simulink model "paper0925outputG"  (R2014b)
settings: Solver=ode3  StartTime=0.0  StopTime=24  FixedStep=1e-2  RelTol=1e-3
libraries: simulink x1

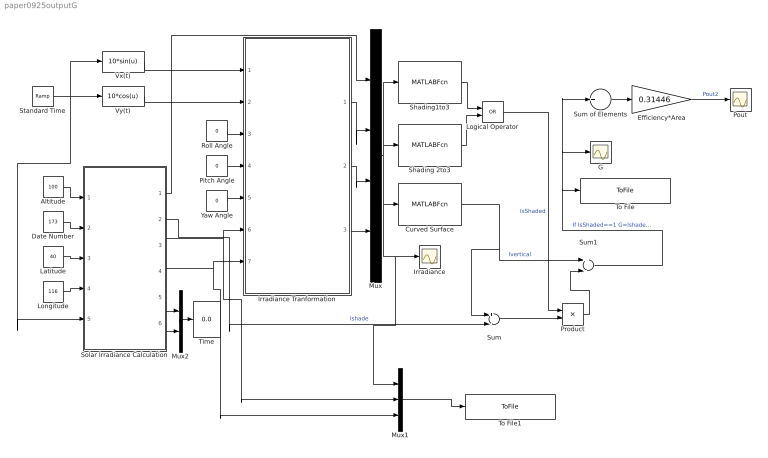
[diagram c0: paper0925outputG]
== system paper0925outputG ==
  Altitude : Constant  Value=100
  Curved Surface : MATLABFcn  MATLABFcn=calculateIcurve  OutputDimensions=18  OutputSignalType=real
  Date Number : Constant  Value=173
  Efficiency*Area : Gain  Gain=0.31446
  G : Scope
  Irradiance : Scope
  Irradiance Tranformation : MATLAB Function  TreatAsAtomicUnit=on
  Latitude : Constant  Value=40
  Logical Operator : Logic  Operator=OR  AllPortsSameDT=off  OutDataTypeStr=boolean
  Longitude : Constant  Value=116
  Mux : Mux  Inputs=[1 1 1 1]
  Mux1 : Mux  Inputs=3
  Mux2 : Mux  Inputs=2
  Pitch Angle : Constant  Value=0
  Pout : Scope
  Product : Product
  Roll Angle : Constant  Value=0
  Shading 2to3 : MATLABFcn  MATLABFcn=calculateIsShaded2  OutputDimensions=18  OutputSignalType=real
  Shading1to3 : MATLABFcn  MATLABFcn=calculateIsShaded1  OutputDimensions=18  OutputSignalType=real
  Solar Irradiance Calculation : MATLAB Function  TreatAsAtomicUnit=on
  Standard Time : simulink/Sources/Ramp  slope=1  start=0  X0=0
  Sum : Sum  Inputs=+-
  Sum of Elements : Sum  Inputs=+
  Sum1 : Sum  Inputs=+-
  Time : Display
  To File : ToFile  Filename=Goverlap100_4.mat  MatrixName=Ir0906
  To File1 : ToFile  Filename=XYZsolar.mat  MatrixName=Ir0906
  Vx(t) : Fcn  Expr=10*sin(u)
  Vy(t) : Fcn  Expr=10*cos(u)
  Yaw Angle : Constant  Value=0
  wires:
  Altitude/1 -> Solar Irradiance Calculation/1(H)
  Date Number/1 -> Solar Irradiance Calculation/2(dn)
  Latitude/1 -> Solar Irradiance Calculation/3(Lati)
  Longitude/1 -> Solar Irradiance Calculation/4(Long)
  Solar Irradiance Calculation/4(Azimuth) -> Mux1/3, Irradiance Tranformation/7(Azimuth)
  Mux2/1 -> Time/1
  Solar Irradiance Calculation/1(I) -> Mux/1
  Solar Irradiance Calculation/5(Tsunrise) -> Mux2/1
  Solar Irradiance Calculation/6(Tsunset) -> Mux2/2
  Irradiance Tranformation/1(Xsolar) -> Mux/2
  Irradiance Tranformation/2(Ysolar) -> Mux/3
  Irradiance Tranformation/3(Zsolar) -> Mux/4
  Vx(t)/1 -> Irradiance Tranformation/1(Vx)
  Vy(t)/1 -> Irradiance Tranformation/2(Vy)
  Pitch Angle/1 -> Irradiance Tranformation/4(Pitch)
  Yaw Angle/1 -> Irradiance Tranformation/5(Yaw)
  Standard Time/1 -> Vx(t)/1, Vy(t)/1, Solar Irradiance Calculation/5(ts)
  Roll Angle/1 -> Irradiance Tranformation/3(Roll)
  Sum of Elements/1 -> Efficiency*Area/1
  Shading1to3/1 -> Logical Operator/1
  Mux/1 -> Mux1/1, Irradiance/1, Curved Surface/1, Shading1to3/1, Shading 2to3/1
  Solar Irradiance Calculation/2(Ishade) -> Sum/2  "Ishade"
  Shading 2to3/1 -> Logical Operator/2
  Curved Surface/1 -> Sum1/1, Sum/1  "Ivertical"
  Logical Operator/1 -> Product/1  "IsShaded"
  Sum/1 -> Product/2
  Product/1 -> Sum1/2
  Sum1/1 -> To File/1, Sum of Elements/1, G/1  "If IsShaded==1 G=Ishaded; else G=Ivertical"
  Efficiency*Area/1 -> Pout/1  "Pout2"
  Mux1/1 -> To File1/1
  Solar Irradiance Calculation/3(Elevation) -> Mux1/2, Irradiance Tranformation/6(Elevation)

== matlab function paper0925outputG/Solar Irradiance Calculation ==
function [I,Ishade,Elevation,Azimuth,Tsunrise,Tsunset] = fcn(H,dn,Lati,Long,ts)
%#codegen
%输入飞行参数（经Long、纬度Lati、高度H、日期dn、标准时间ts）
%输出照射情况（高度角Elevatio、方位角Azimuth、垂直辐照度I)
%输出一天的统计情况

Isc =1367;%太阳常数，W/m2
dec=23.45*sind(360*(dn+284)/365);%计算赤纬角dec
b = 360*(dn-81)/365;
e = 9.87*sind(2*b)-7.53*cosd(b)-1.5*sind(b); %e为平太阳和真太阳时差，单位分钟
tn=ts+e/60+(Long-120)/15;  %ts为标准时间，tn为真太阳时
%tn为当地标准时间（北京）ts = t + e./60+（或-）(Long-Ls)./15
%Ls为当地地区标准时间位置的地理经度，中国为东八区，Ls为120；对于正负号，东半球为正，西半球为负

omega = 15*(tn - 12);%太阳时角
%计算太阳高度角
Elevation = asind(sind(Lati).*sind(dec)+cosd(Lati).*cosd(dec).*cosd(omega));

%计算太阳方位角
%方位角的反三角函数，在上午，时角<0,方位角范围在0-180，下午时角>0,方位角可能超过180，acos出现折线
%此处在经度变化时可能仍有问题。
c2=(sind(dec)-sind(Elevation).*sind(Lati))./(cosd(Elevation).*cosd(Lati));
if(omega<0)
    Azimuth =acosd(c2);
else
    Azimuth =-acosd(c2);
end

xi0 = 1+0.033*cosd(360*dn/365);%计算日地距离xi0
%计算大气质量AMh
AM = 1./(sind(Elevation));  %不考虑高度的大气质量
etah = real((1 - 0.0065/288*H).^5.256);  %大气高度修正系数
intvari1 = 614*sind(Elevation); 
intvari2 = 1229 + intvari1.^2;
am0 = intvari2.^0.5 - 614*sind(Elevation); % 计算海平面上大气质量am0;
% 计算H高度下的大气质量
if(Elevation<30)   
    AMh = am0.*etah;
else
    AMh = AM.*etah;
end
%计算大气透明度系数PCO
intvari3 = exp(-0.65*AMh);
intvari4 = exp(-0.096*AMh);
PCO = 0.56*(intvari3 + intvari4)*0.85;

I = Isc*xi0.*PCO;%计算太阳辐射强度I

% 计算当地太阳时日出日落时间 ts1 and ts2 ;
ts1 = acosd(tand(Lati)*tand(dec))/15;
ts2 = 24-ts1;
Tsunrise = ts1-e./60-(Long-120)./15; %计算标准日出时间
Tsunset = ts2-e./60-(Long-120)./15; %计算标准日落时间
Ishade=100/(pi/2).*atan(I/(100/(pi/2)));

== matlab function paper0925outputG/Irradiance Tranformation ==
function [Xsolar,Ysolar,Zsolar] = fcn(Vx,Vy,Roll,Pitch,Yaw,Elevation,Azimuth)
%#codegen
%输入飞行速度、姿态、太阳高度角、方位角
%输出Xsolar,Ysolar,Zsolar为光线照射方向的坐标分量
%方位角定义为从北方，顺时针为正
%地轴系E被定义为北方x轴，东y，z向下指向地心

%从机体轴系到牵连垂直坐标系
TVB=[cosd(Pitch).*cosd(Yaw),-cosd(Roll).*sind(Yaw)+sind(Roll).*sind(Pitch).*cosd(Yaw),sind(Roll).*sind(Yaw)+cosd(Roll).*sind(Pitch).*cosd(Yaw);
    cosd(Pitch).*sind(Yaw),cosd(Roll).*cosd(Yaw)+sind(Roll).*sind(Pitch).*sind(Yaw),-sind(Roll).*cosd(Yaw)+cosd(Roll).*sind(Pitch).*sind(Yaw);
    -sind(Pitch),sind(Roll).*cosd(Pitch),cosd(Roll).*cosd(Pitch)];
%从牵连垂直坐标系到地轴系
TEV=[Vx/(Vx^2+Vy^2)^0.5 Vy/(Vx^2+Vy^2)^0.5 0;
    -Vy/(Vx^2+Vy^2)^0.5 Vx/(Vx^2+Vy^2)^0.5 0;
    0 0 1];
%太阳照射方向矢量
SolarDirection=TVB'*TEV'*[-cosd(Elevation)*cosd(Azimuth);
    -cosd(Elevation)*sind(Azimuth);
    sind(Elevation)];
Xsolar=SolarDirection(1);
Ysolar=SolarDirection(2);
Zsolar=SolarDirection(3);
